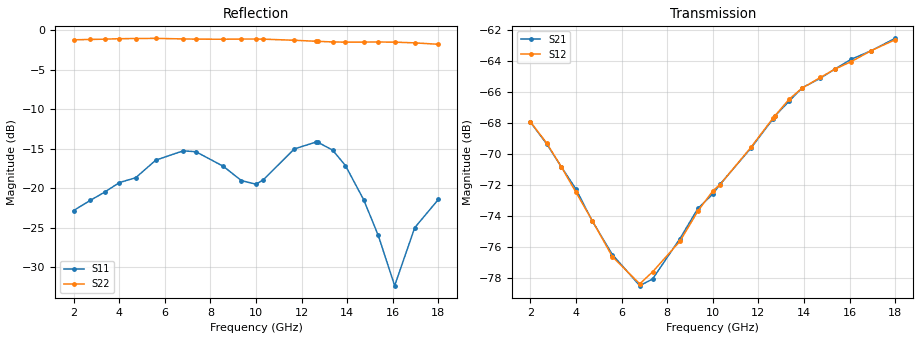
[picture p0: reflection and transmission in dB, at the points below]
!Keysight Technologies,P5004A,MY58100454,A.15.10.06
!Date: Monday, July 18, 2022 10:32:37
!Correction: S11(C  2-Port  )
!S21(C  2-Port  )
!S12(C  2-Port  )
!S22(C  2-Port  )
!S2P File: Measurements: S11, S21, S12, S22:
# Hz S  dB  R 50
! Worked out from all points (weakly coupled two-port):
!   201 points, 2 GHz to 18 GHz, reference 50 ohm
!   highest |S21| = -62.53 dB at 18 GHz (marker M1); lowest = -78.5 dB at 6.8 GHz (marker M2)
!   lowest |S11| = -32.3 dB at 16.08 GHz (marker M3), VSWR 1.05, Z = 47.8 + j0.851 ohm
!   |S11| at or under -10 dB: start of sweep to end of sweep
!   |S22| runs from -1.8 to -1.0 dB; largest |S21 - S12| = 2.2e-05
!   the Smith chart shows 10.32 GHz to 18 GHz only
!   S11 on the Smith chart (normalised r, x): 10.32 GHz: 0.80, +0.02; 11.68 GHz: 0.89, +0.32; 12.64 GHz: 1.33, +0.32; 18 GHz: 1.18, -0.03
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2e9  -22.81 -64.4  -67.94 -101.2  -67.92 -100.7  -1.21 71.6
2.72e9  -21.54 -100.8  -69.36 -145.9  -69.31 -145.8  -1.17 31.6
3.36e9  -20.48 -123.4  -70.84 178.7  -70.84 178.2  -1.13 -3.2
4e9  -19.28 -160.7  -72.27 146.7  -72.48 146.4  -1.07 -37.7
4.72e9  -18.66 166.0  -74.35 113.5  -74.32 113.3  -1.05 -76.6
5.6e9  -16.44 114.2  -76.51 82.2  -76.65 82.4  -1.03 -124.1
6.8e9  -15.26 31.4  -78.52 50.0  -78.40 49.7  -1.10 171.0
7.36e9  -15.37 -9.2  -78.09 37.0  -77.63 37.2  -1.13 141.2
8.56e9  -17.21 -95.1  -75.48 0.9  -75.65 -0.4  -1.14 78.4
9.36e9  -19.03 -142.8  -73.51 -33.3  -73.67 -32.5  -1.12 37.3
1e10  -19.48 -171.2  -72.60 -61.3  -72.40 -60.7  -1.12 4.5
1.032e10  -18.92 175.3  -71.97 -76.9  -71.98 -75.8  -1.13 -11.9
1.168e10  -15.02 99.1  -69.62 -134.2  -69.57 -135.2  -1.27 -82.1
1.264e10  -14.14 36.6  -67.75 178.5  -67.69 178.5  -1.40 -133.0
1.272e10  -14.19 31.4  -67.56 173.5  -67.55 173.6  -1.41 -137.3
1.336e10  -15.17 -9.3  -66.58 139.8  -66.45 140.4  -1.48 -172.0
1.392e10  -17.12 -42.5  -65.73 111.4  -65.75 110.2  -1.51 157.2
1.472e10  -21.44 -84.2  -65.11 68.4  -65.06 68.8  -1.50 113.3
1.536e10  -25.96 -118.4  -64.51 35.6  -64.52 36.0  -1.49 78.6
1.608e10  -32.32 158.4  -63.88 -0.8  -64.03 -0.6  -1.51 40.9
1.696e10  -24.98 44.8  -63.32 -45.4  -63.32 -44.6  -1.60 -3.2
1.8e10  -21.40 -9.3  -62.53 -96.0  -62.62 -96.4  -1.78 -53.9
